# i3dPDK_A16K CFET_3T cell LEF (1x), from BE/CFET/3T/i3dPDK_A16K_0V7_27C_3T.lef:
# SITE i3d_16A added, coordinates on the 0.5nm grid (signal pins snapped outward, OBS outward).
# i3dPDK_A16K v1.0 (CC BY-NC-SA 4.0, Prof. Taigon Song, I3D VLSI Lab, KNU)
# Read after i3dPDK_A16K_3T_tech.lef.
VERSION 5.8 ;
BUSBITCHARS "[]" ;
DIVIDERCHAR "/" ;


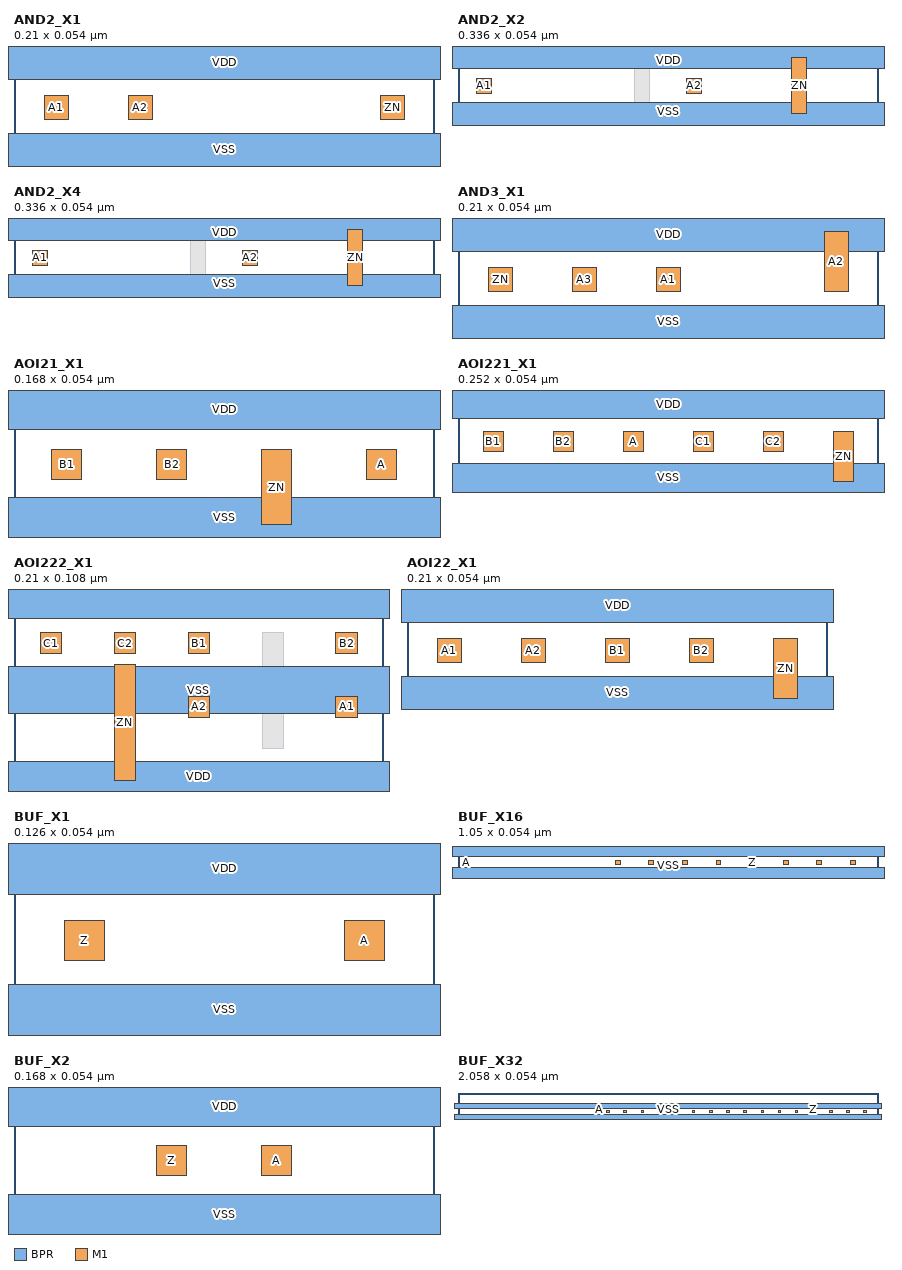
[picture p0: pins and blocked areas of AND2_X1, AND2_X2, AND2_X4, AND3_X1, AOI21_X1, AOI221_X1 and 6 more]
MACRO AND2_X1
  CLASS CORE ;
  FOREIGN AND2_X1 0 0 ;
  ORIGIN 0.0000 0.0000 ;
  SIZE 0.2100 BY 0.0540 ;
  SYMMETRY X Y ;
  SITE i3d_16A ;
  PIN VSS
    DIRECTION INOUT ;
    USE GROUND ;
    PORT
      LAYER BPR ;
        RECT -0.0160 -0.0135 0.2260 0.0135 ;
    END
  END VSS
  PIN VDD
    DIRECTION INOUT ;
    USE POWER ;
    PORT
      LAYER BPR ;
        RECT -0.0160 0.0405 0.2260 0.0675 ;
    END
  END VDD
  PIN A2
    DIRECTION INPUT ;
    USE SIGNAL ;
    PORT
      LAYER M1 ;
        RECT 0.0570 0.0205 0.0690 0.0325 ;
    END
  END A2
  PIN A1
    DIRECTION INPUT ;
    USE SIGNAL ;
    PORT
      LAYER M1 ;
        RECT 0.0150 0.0205 0.0270 0.0325 ;
    END
  END A1
  PIN ZN
    DIRECTION OUTPUT ;
    USE SIGNAL ;
    PORT
      LAYER M1 ;
        RECT 0.1830 0.0205 0.1950 0.0325 ;
    END
  END ZN
END AND2_X1

MACRO AND2_X2
  CLASS CORE ;
  FOREIGN AND2_X2 0 0 ;
  ORIGIN 0.0000 0.0000 ;
  SIZE 0.3360 BY 0.0540 ;
  SYMMETRY X Y ;
  SITE i3d_16A ;
  PIN VSS
    DIRECTION INOUT ;
    USE GROUND ;
    PORT
      LAYER BPR ;
        RECT -0.0160 -0.0135 0.3530 0.0135 ;
    END
  END VSS
  PIN VDD
    DIRECTION INOUT ;
    USE POWER ;
    PORT
      LAYER BPR ;
        RECT -0.0160 0.0405 0.3530 0.0675 ;
    END
  END VDD
  PIN A2
    DIRECTION INPUT ;
    USE SIGNAL ;
    PORT
      LAYER M1 ;
        RECT 0.1830 0.0205 0.1950 0.0325 ;
    END
  END A2
  PIN A1
    DIRECTION INPUT ;
    USE SIGNAL ;
    PORT
      LAYER M1 ;
        RECT 0.0150 0.0205 0.0270 0.0325 ;
    END
  END A1
  PIN ZN
    DIRECTION OUTPUT ;
    USE SIGNAL ;
    PORT
      LAYER M1 ;
        RECT 0.2670 0.0045 0.2790 0.0495 ;
    END
  END ZN
  OBS
    LAYER M1 ;
      RECT 0.1410 0.0025 0.1530 0.0505 ;
  END
END AND2_X2

MACRO AND2_X4
  CLASS CORE ;
  FOREIGN AND2_X4 0 0 ;
  ORIGIN 0.0000 0.0000 ;
  SIZE 0.3360 BY 0.0540 ;
  SYMMETRY X Y ;
  SITE i3d_16A ;
  PIN VSS
    DIRECTION INOUT ;
    USE GROUND ;
    PORT
      LAYER BPR ;
        RECT -0.0160 -0.0135 0.3530 0.0135 ;
    END
  END VSS
  PIN VDD
    DIRECTION INOUT ;
    USE POWER ;
    PORT
      LAYER BPR ;
        RECT -0.0160 0.0405 0.3530 0.0675 ;
    END
  END VDD
  PIN A2
    DIRECTION INPUT ;
    USE SIGNAL ;
    PORT
      LAYER M1 ;
        RECT 0.1830 0.0205 0.1950 0.0325 ;
    END
  END A2
  PIN A1
    DIRECTION INPUT ;
    USE SIGNAL ;
    PORT
      LAYER M1 ;
        RECT 0.0150 0.0205 0.0270 0.0325 ;
    END
  END A1
  PIN ZN
    DIRECTION OUTPUT ;
    USE SIGNAL ;
    PORT
      LAYER M1 ;
        RECT 0.2670 0.0045 0.2790 0.0495 ;
    END
  END ZN
  OBS
    LAYER M1 ;
      RECT 0.1410 0.0025 0.1530 0.0505 ;
  END
END AND2_X4

MACRO AND3_X1
  CLASS CORE ;
  FOREIGN AND3_X1 0 0 ;
  ORIGIN 0.0000 0.0000 ;
  SIZE 0.2100 BY 0.0540 ;
  SYMMETRY X Y ;
  SITE i3d_16A ;
  PIN VDD
    DIRECTION INOUT ;
    USE POWER ;
    PORT
      LAYER BPR ;
        RECT -0.0160 0.0405 0.2260 0.0675 ;
    END
  END VDD
  PIN VSS
    DIRECTION INOUT ;
    USE GROUND ;
    PORT
      LAYER BPR ;
        RECT -0.0160 -0.0135 0.2260 0.0135 ;
    END
  END VSS
  PIN A3
    DIRECTION INPUT ;
    USE SIGNAL ;
    PORT
      LAYER M1 ;
        RECT 0.0570 0.0205 0.0690 0.0325 ;
    END
  END A3
  PIN A1
    DIRECTION INPUT ;
    USE SIGNAL ;
    PORT
      LAYER M1 ;
        RECT 0.0990 0.0205 0.1110 0.0325 ;
    END
  END A1
  PIN ZN
    DIRECTION OUTPUT ;
    USE SIGNAL ;
    PORT
      LAYER M1 ;
        RECT 0.0150 0.0205 0.0270 0.0325 ;
    END
  END ZN
  PIN A2
    DIRECTION INPUT ;
    USE SIGNAL ;
    PORT
      LAYER M1 ;
        RECT 0.1830 0.0205 0.1950 0.0505 ;
    END
  END A2
END AND3_X1

MACRO AOI21_X1
  CLASS CORE ;
  FOREIGN AOI21_X1 0 0 ;
  ORIGIN 0.0000 0.0000 ;
  SIZE 0.1680 BY 0.0540 ;
  SYMMETRY X Y ;
  SITE i3d_16A ;
  PIN VSS
    DIRECTION INOUT ;
    USE GROUND ;
    PORT
      LAYER BPR ;
        RECT -0.0160 -0.0135 0.1840 0.0135 ;
    END
  END VSS
  PIN VDD
    DIRECTION INOUT ;
    USE POWER ;
    PORT
      LAYER BPR ;
        RECT -0.0160 0.0405 0.1840 0.0675 ;
    END
  END VDD
  PIN B2
    DIRECTION INPUT ;
    USE SIGNAL ;
    PORT
      LAYER M1 ;
        RECT 0.0570 0.0205 0.0690 0.0325 ;
    END
  END B2
  PIN B1
    DIRECTION INPUT ;
    USE SIGNAL ;
    PORT
      LAYER M1 ;
        RECT 0.0150 0.0205 0.0270 0.0325 ;
    END
  END B1
  PIN ZN
    DIRECTION OUTPUT ;
    USE SIGNAL ;
    PORT
      LAYER M1 ;
        RECT 0.0990 0.0025 0.1110 0.0325 ;
    END
  END ZN
  PIN A
    DIRECTION INPUT ;
    USE SIGNAL ;
    PORT
      LAYER M1 ;
        RECT 0.1410 0.0205 0.1530 0.0325 ;
    END
  END A
END AOI21_X1

MACRO AOI221_X1
  CLASS CORE ;
  FOREIGN AOI221_X1 0 0 ;
  ORIGIN 0.0000 0.0000 ;
  SIZE 0.2520 BY 0.0540 ;
  SYMMETRY X Y ;
  SITE i3d_16A ;
  PIN VSS
    DIRECTION INOUT ;
    USE GROUND ;
    PORT
      LAYER BPR ;
        RECT -0.0160 -0.0135 0.2680 0.0135 ;
    END
  END VSS
  PIN VDD
    DIRECTION INOUT ;
    USE POWER ;
    PORT
      LAYER BPR ;
        RECT -0.0160 0.0405 0.2680 0.0675 ;
    END
  END VDD
  PIN C2
    DIRECTION INPUT ;
    USE SIGNAL ;
    PORT
      LAYER M1 ;
        RECT 0.1830 0.0205 0.1950 0.0325 ;
    END
  END C2
  PIN A
    DIRECTION INPUT ;
    USE SIGNAL ;
    PORT
      LAYER M1 ;
        RECT 0.0990 0.0205 0.1110 0.0325 ;
    END
  END A
  PIN C1
    DIRECTION INPUT ;
    USE SIGNAL ;
    PORT
      LAYER M1 ;
        RECT 0.1410 0.0205 0.1530 0.0325 ;
    END
  END C1
  PIN B1
    DIRECTION INPUT ;
    USE SIGNAL ;
    PORT
      LAYER M1 ;
        RECT 0.0150 0.0205 0.0270 0.0325 ;
    END
  END B1
  PIN ZN
    DIRECTION OUTPUT ;
    USE SIGNAL ;
    PORT
      LAYER M1 ;
        RECT 0.2250 0.0025 0.2370 0.0325 ;
    END
  END ZN
  PIN B2
    DIRECTION INPUT ;
    USE SIGNAL ;
    PORT
      LAYER M1 ;
        RECT 0.0570 0.0205 0.0690 0.0325 ;
    END
  END B2
END AOI221_X1

MACRO AOI222_X1
  CLASS CORE ;
  FOREIGN AOI222_X1 0 0 ;
  ORIGIN 0.0000 0.0000 ;
  SIZE 0.2100 BY 0.1080 ;
  SYMMETRY X Y ;
  SITE i3d_16A ;
  PIN VDD
    DIRECTION INOUT ;
    USE POWER ;
    PORT
      LAYER BPR ;
        RECT -0.0160 -0.0135 0.2260 0.0135 ;
        RECT -0.0160 0.0945 0.2260 0.1215 ;
    END
  END VDD
  PIN VSS
    DIRECTION INOUT ;
    USE GROUND ;
    PORT
      LAYER BPR ;
        RECT -0.0160 0.0405 0.2260 0.0675 ;
    END
  END VSS
  PIN ZN
    DIRECTION OUTPUT ;
    USE SIGNAL ;
    PORT
      LAYER M1 ;
        RECT 0.0570 0.0025 0.0690 0.0685 ;
    END
  END ZN
  PIN A2
    DIRECTION INPUT ;
    USE SIGNAL ;
    PORT
      LAYER M1 ;
        RECT 0.0990 0.0385 0.1110 0.0505 ;
    END
  END A2
  PIN A1
    DIRECTION INPUT ;
    USE SIGNAL ;
    PORT
      LAYER M1 ;
        RECT 0.1830 0.0385 0.1950 0.0505 ;
    END
  END A1
  PIN B1
    DIRECTION INPUT ;
    USE SIGNAL ;
    PORT
      LAYER M1 ;
        RECT 0.0990 0.0745 0.1110 0.0865 ;
    END
  END B1
  PIN B2
    DIRECTION INPUT ;
    USE SIGNAL ;
    PORT
      LAYER M1 ;
        RECT 0.1830 0.0745 0.1950 0.0865 ;
    END
  END B2
  PIN C1
    DIRECTION INPUT ;
    USE SIGNAL ;
    PORT
      LAYER M1 ;
        RECT 0.0150 0.0745 0.0270 0.0865 ;
    END
  END C1
  PIN C2
    DIRECTION INPUT ;
    USE SIGNAL ;
    PORT
      LAYER M1 ;
        RECT 0.0570 0.0745 0.0690 0.0865 ;
    END
  END C2
  OBS
    LAYER M1 ;
      RECT 0.1410 0.0205 0.1530 0.0325 ;
      RECT 0.1410 0.0205 0.1530 0.0865 ;
  END
END AOI222_X1

MACRO AOI22_X1
  CLASS CORE ;
  FOREIGN AOI22_X1 0 0 ;
  ORIGIN 0.0000 0.0000 ;
  SIZE 0.2100 BY 0.0540 ;
  SYMMETRY X Y ;
  SITE i3d_16A ;
  PIN VDD
    DIRECTION INOUT ;
    USE POWER ;
    PORT
      LAYER BPR ;
        RECT -0.0160 0.0405 0.2260 0.0675 ;
    END
  END VDD
  PIN VSS
    DIRECTION INOUT ;
    USE GROUND ;
    PORT
      LAYER BPR ;
        RECT -0.0160 -0.0135 0.2260 0.0135 ;
    END
  END VSS
  PIN A2
    DIRECTION INPUT ;
    USE SIGNAL ;
    PORT
      LAYER M1 ;
        RECT 0.0570 0.0205 0.0690 0.0325 ;
    END
  END A2
  PIN ZN
    DIRECTION OUTPUT ;
    USE SIGNAL ;
    PORT
      LAYER M1 ;
        RECT 0.1830 0.0025 0.1950 0.0325 ;
    END
  END ZN
  PIN A1
    DIRECTION INPUT ;
    USE SIGNAL ;
    PORT
      LAYER M1 ;
        RECT 0.0150 0.0205 0.0270 0.0325 ;
    END
  END A1
  PIN B2
    DIRECTION INPUT ;
    USE SIGNAL ;
    PORT
      LAYER M1 ;
        RECT 0.1410 0.0205 0.1530 0.0325 ;
    END
  END B2
  PIN B1
    DIRECTION INPUT ;
    USE SIGNAL ;
    PORT
      LAYER M1 ;
        RECT 0.0990 0.0205 0.1110 0.0325 ;
    END
  END B1
END AOI22_X1

MACRO BUF_X1
  CLASS CORE ;
  FOREIGN BUF_X1 0 0 ;
  ORIGIN 0.0000 0.0000 ;
  SIZE 0.1260 BY 0.0540 ;
  SYMMETRY X Y ;
  SITE i3d_16A ;
  PIN VSS
    DIRECTION INOUT ;
    USE GROUND ;
    PORT
      LAYER BPR ;
        RECT -0.0160 -0.0135 0.1420 0.0135 ;
    END
  END VSS
  PIN VDD
    DIRECTION INOUT ;
    USE POWER ;
    PORT
      LAYER BPR ;
        RECT -0.0160 0.0405 0.1420 0.0675 ;
    END
  END VDD
  PIN Z
    DIRECTION OUTPUT ;
    USE SIGNAL ;
    PORT
      LAYER M1 ;
        RECT 0.0150 0.0205 0.0270 0.0325 ;
    END
  END Z
  PIN A
    DIRECTION INPUT ;
    USE SIGNAL ;
    PORT
      LAYER M1 ;
        RECT 0.0990 0.0205 0.1110 0.0325 ;
    END
  END A
END BUF_X1

MACRO BUF_X16
  CLASS CORE ;
  FOREIGN BUF_X16 0 0 ;
  ORIGIN 0.0000 0.0000 ;
  SIZE 1.0500 BY 0.0540 ;
  SYMMETRY X Y ;
  SITE i3d_16A ;
  PIN VDD
    DIRECTION INOUT ;
    USE POWER ;
    PORT
      LAYER BPR ;
        RECT -0.0160 0.0405 1.0660 0.0675 ;
    END
  END VDD
  PIN VSS
    DIRECTION INOUT ;
    USE GROUND ;
    PORT
      LAYER BPR ;
        RECT -0.0160 -0.0135 1.0660 0.0135 ;
    END
  END VSS
  PIN Z
    DIRECTION OUTPUT ;
    USE SIGNAL ;
    PORT
      LAYER M1 ;
        RECT 0.7290 0.0205 0.7410 0.0325 ;
        RECT 0.8130 0.0205 0.8250 0.0325 ;
        RECT 0.9810 0.0205 0.9930 0.0325 ;
        RECT 0.8970 0.0205 0.9090 0.0325 ;
        RECT 0.4770 0.0205 0.4890 0.0325 ;
        RECT 0.3930 0.0205 0.4050 0.0325 ;
        RECT 0.6450 0.0205 0.6570 0.0325 ;
        RECT 0.5610 0.0205 0.5730 0.0325 ;
    END
  END Z
  PIN A
    DIRECTION INPUT ;
    USE SIGNAL ;
    PORT
      LAYER M1 ;
        RECT 0.0150 0.0205 0.0270 0.0325 ;
    END
  END A
END BUF_X16

MACRO BUF_X2
  CLASS CORE ;
  FOREIGN BUF_X2 0 0 ;
  ORIGIN 0.0000 0.0000 ;
  SIZE 0.1680 BY 0.0540 ;
  SYMMETRY X Y ;
  SITE i3d_16A ;
  PIN VDD
    DIRECTION INOUT ;
    USE POWER ;
    PORT
      LAYER BPR ;
        RECT -0.0160 0.0405 0.1840 0.0675 ;
    END
  END VDD
  PIN VSS
    DIRECTION INOUT ;
    USE GROUND ;
    PORT
      LAYER BPR ;
        RECT -0.0160 -0.0135 0.1840 0.0135 ;
    END
  END VSS
  PIN A
    DIRECTION INPUT ;
    USE SIGNAL ;
    PORT
      LAYER M1 ;
        RECT 0.0990 0.0210 0.1110 0.0330 ;
    END
  END A
  PIN Z
    DIRECTION OUTPUT ;
    USE SIGNAL ;
    PORT
      LAYER M1 ;
        RECT 0.0570 0.0210 0.0690 0.0330 ;
    END
  END Z
END BUF_X2

MACRO BUF_X32
  CLASS CORE ;
  FOREIGN BUF_X32 0 0 ;
  ORIGIN 0.0000 0.0000 ;
  SIZE 2.0580 BY 0.0540 ;
  SYMMETRY X Y ;
  SITE i3d_16A ;
  PIN VSS
    DIRECTION INOUT ;
    USE GROUND ;
    PORT
      LAYER BPR ;
        RECT -0.0160 -0.0135 2.0740 0.0135 ;
    END
  END VSS
  PIN VDD
    DIRECTION INOUT ;
    USE POWER ;
    PORT
      LAYER BPR ;
        RECT -0.0160 0.0405 2.0740 0.0675 ;
    END
  END VDD
  PIN Z
    DIRECTION OUTPUT ;
    USE SIGNAL ;
    PORT
      LAYER M1 ;
        RECT 1.7370 0.0205 1.7490 0.0325 ;
        RECT 1.8210 0.0205 1.8330 0.0325 ;
        RECT 1.9890 0.0205 2.0010 0.0325 ;
        RECT 1.9050 0.0205 1.9170 0.0325 ;
        RECT 1.4850 0.0205 1.4970 0.0325 ;
        RECT 1.4010 0.0205 1.4130 0.0325 ;
        RECT 1.6530 0.0205 1.6650 0.0325 ;
        RECT 1.5690 0.0205 1.5810 0.0325 ;
        RECT 1.2330 0.0205 1.2450 0.0325 ;
        RECT 1.3170 0.0205 1.3290 0.0325 ;
        RECT 1.1490 0.0205 1.1610 0.0325 ;
        RECT 1.0650 0.0205 1.0770 0.0325 ;
        RECT 0.7290 0.0205 0.7410 0.0325 ;
        RECT 0.8130 0.0205 0.8250 0.0325 ;
        RECT 0.9810 0.0205 0.9930 0.0325 ;
        RECT 0.8970 0.0205 0.9090 0.0325 ;
    END
  END Z
  PIN A
    DIRECTION INPUT ;
    USE SIGNAL ;
    PORT
      LAYER M1 ;
        RECT 0.6870 0.0205 0.6990 0.0325 ;
    END
  END A
END BUF_X32

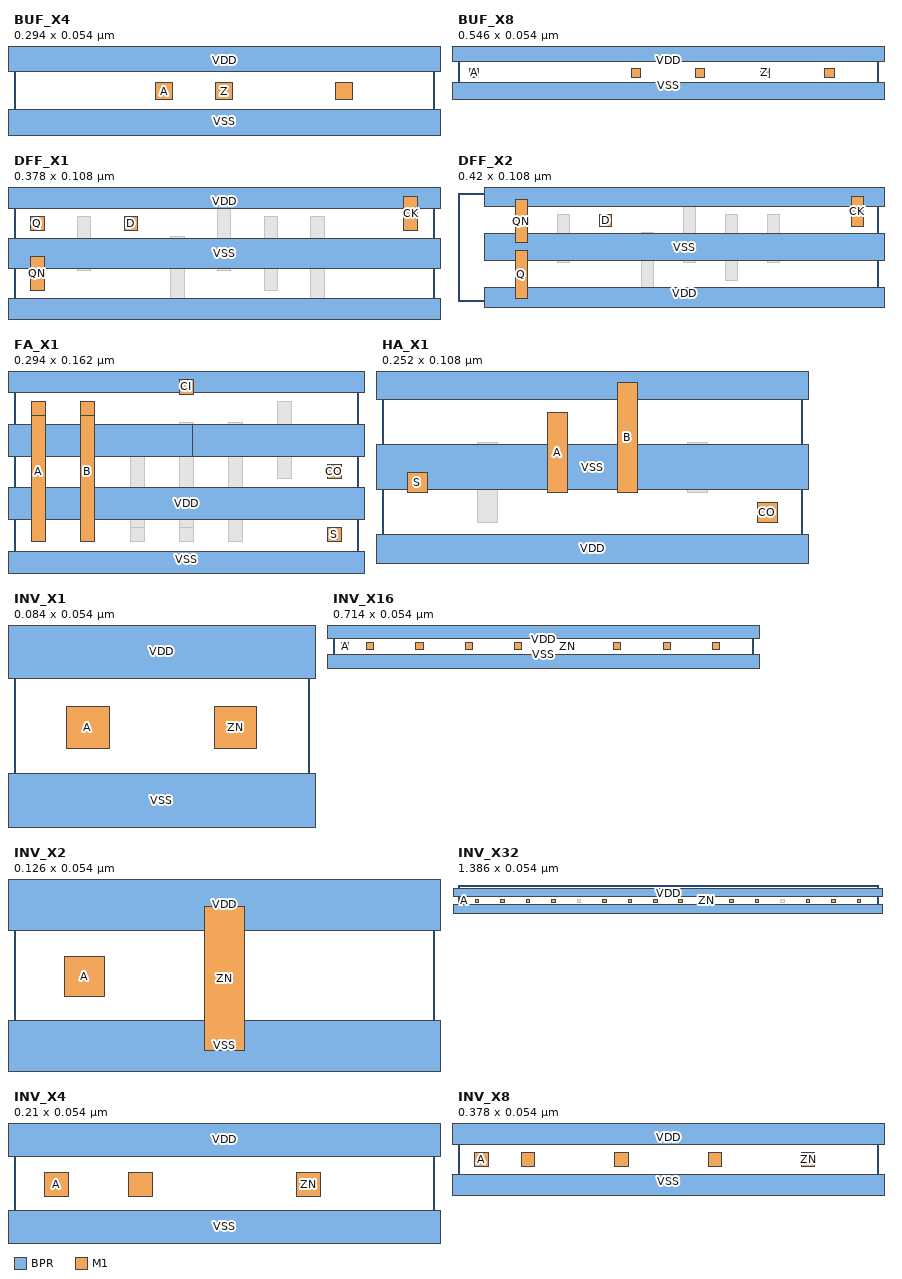
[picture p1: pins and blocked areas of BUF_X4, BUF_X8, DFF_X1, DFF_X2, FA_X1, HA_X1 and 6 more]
MACRO BUF_X4
  CLASS CORE ;
  FOREIGN BUF_X4 0 0 ;
  ORIGIN 0.0000 0.0000 ;
  SIZE 0.2940 BY 0.0540 ;
  SYMMETRY X Y ;
  SITE i3d_16A ;
  PIN VDD
    DIRECTION INOUT ;
    USE POWER ;
    PORT
      LAYER BPR ;
        RECT -0.0160 0.0405 0.3100 0.0675 ;
    END
  END VDD
  PIN VSS
    DIRECTION INOUT ;
    USE GROUND ;
    PORT
      LAYER BPR ;
        RECT -0.0160 -0.0135 0.3100 0.0135 ;
    END
  END VSS
  PIN A
    DIRECTION INPUT ;
    USE SIGNAL ;
    PORT
      LAYER M1 ;
        RECT 0.0990 0.0205 0.1110 0.0325 ;
    END
  END A
  PIN Z
    DIRECTION OUTPUT ;
    USE SIGNAL ;
    PORT
      LAYER M1 ;
        RECT 0.2250 0.0205 0.2370 0.0325 ;
        RECT 0.1410 0.0205 0.1530 0.0325 ;
    END
  END Z
END BUF_X4

MACRO BUF_X8
  CLASS CORE ;
  FOREIGN BUF_X8 0 0 ;
  ORIGIN 0.0000 0.0000 ;
  SIZE 0.5460 BY 0.0540 ;
  SYMMETRY X Y ;
  SITE i3d_16A ;
  PIN VSS
    DIRECTION INOUT ;
    USE GROUND ;
    PORT
      LAYER BPR ;
        RECT -0.0160 -0.0135 0.5620 0.0135 ;
    END
  END VSS
  PIN VDD
    DIRECTION INOUT ;
    USE POWER ;
    PORT
      LAYER BPR ;
        RECT -0.0160 0.0405 0.5620 0.0675 ;
    END
  END VDD
  PIN Z
    DIRECTION OUTPUT ;
    USE SIGNAL ;
    PORT
      LAYER M1 ;
        RECT 0.3930 0.0205 0.4050 0.0325 ;
        RECT 0.4770 0.0205 0.4890 0.0325 ;
        RECT 0.3090 0.0205 0.3210 0.0325 ;
        RECT 0.2250 0.0205 0.2370 0.0325 ;
    END
  END Z
  PIN A
    DIRECTION INPUT ;
    USE SIGNAL ;
    PORT
      LAYER M1 ;
        RECT 0.0150 0.0205 0.0270 0.0325 ;
    END
  END A
END BUF_X8

MACRO DFF_X1
  CLASS CORE ;
  FOREIGN DFF_X1 0 0 ;
  ORIGIN 0.0000 0.0000 ;
  SIZE 0.3780 BY 0.1080 ;
  SYMMETRY X Y ;
  SITE i3d_16A ;
  PIN VDD
    DIRECTION INOUT ;
    USE POWER ;
    PORT
      LAYER BPR ;
        RECT -0.0160 0.0945 0.3940 0.1215 ;
        RECT -0.0160 -0.0135 0.3940 0.0135 ;
    END
  END VDD
  PIN VSS
    DIRECTION INOUT ;
    USE GROUND ;
    PORT
      LAYER BPR ;
        RECT -0.0160 0.0405 0.3940 0.0675 ;
    END
  END VSS
  PIN CK
    DIRECTION INPUT ;
    USE CLOCK ;
    PORT
      LAYER M1 ;
        RECT 0.3510 0.0745 0.3630 0.1045 ;
    END
  END CK
  PIN D
    DIRECTION INPUT ;
    USE SIGNAL ;
    PORT
      LAYER M1 ;
        RECT 0.0990 0.0745 0.1110 0.0865 ;
    END
  END D
  PIN QN
    DIRECTION OUTPUT ;
    USE SIGNAL ;
    PORT
      LAYER M1 ;
        RECT 0.0150 0.0205 0.0270 0.0505 ;
    END
  END QN
  PIN Q
    DIRECTION OUTPUT ;
    USE SIGNAL ;
    PORT
      LAYER M1 ;
        RECT 0.0150 0.0745 0.0270 0.0865 ;
    END
  END Q
  OBS
    LAYER M1 ;
      RECT 0.2250 0.0205 0.2370 0.0865 ;
      RECT 0.1410 0.0025 0.1530 0.0685 ;
      RECT 0.2670 0.0025 0.2790 0.0865 ;
      RECT 0.1830 0.0385 0.1950 0.1045 ;
      RECT 0.0570 0.0385 0.0690 0.0865 ;
  END
END DFF_X1

MACRO DFF_X2
  CLASS CORE ;
  FOREIGN DFF_X2 0 0 ;
  ORIGIN 0.0000 0.0000 ;
  SIZE 0.4200 BY 0.1080 ;
  SYMMETRY X Y ;
  SITE i3d_16A ;
  PIN VDD
    DIRECTION INOUT ;
    USE POWER ;
    PORT
      LAYER BPR ;
        RECT 0.0260 0.0945 0.4360 0.1215 ;
        RECT 0.0260 -0.0135 0.4360 0.0135 ;
    END
  END VDD
  PIN VSS
    DIRECTION INOUT ;
    USE GROUND ;
    PORT
      LAYER BPR ;
        RECT 0.0260 0.0405 0.4360 0.0675 ;
    END
  END VSS
  PIN CK
    DIRECTION INPUT ;
    USE CLOCK ;
    PORT
      LAYER M1 ;
        RECT 0.3930 0.0745 0.4050 0.1045 ;
    END
  END CK
  PIN D
    DIRECTION INPUT ;
    USE SIGNAL ;
    PORT
      LAYER M1 ;
        RECT 0.1410 0.0745 0.1530 0.0865 ;
    END
  END D
  PIN QN
    DIRECTION OUTPUT ;
    USE SIGNAL ;
    PORT
      LAYER M1 ;
        RECT 0.0570 0.0585 0.0690 0.1015 ;
    END
  END QN
  PIN Q
    DIRECTION OUTPUT ;
    USE SIGNAL ;
    PORT
      LAYER M1 ;
        RECT 0.0570 0.0025 0.0690 0.0505 ;
    END
  END Q
  OBS
    LAYER M1 ;
      RECT 0.2670 0.0205 0.2790 0.0865 ;
      RECT 0.1830 0.0025 0.1950 0.0685 ;
      RECT 0.3090 0.0385 0.3210 0.0865 ;
      RECT 0.2250 0.0385 0.2370 0.1045 ;
      RECT 0.0990 0.0385 0.1110 0.0865 ;
  END
END DFF_X2

MACRO FA_X1
  CLASS CORE ;
  FOREIGN FA_X1 0 0 ;
  ORIGIN 0.0000 0.0000 ;
  SIZE 0.2940 BY 0.1620 ;
  SYMMETRY X Y ;
  SITE i3d_16A ;
  PIN VDD
    DIRECTION INOUT ;
    USE POWER ;
    PORT
      LAYER BPR ;
        RECT 0.0260 0.0405 0.3100 0.0675 ;
        RECT -0.0160 0.1485 0.3100 0.1755 ;
        RECT -0.0160 0.0405 0.3100 0.0675 ;
    END
  END VDD
  PIN VSS
    DIRECTION INOUT ;
    USE GROUND ;
    PORT
      LAYER BPR ;
        RECT -0.0160 0.0945 0.3100 0.1215 ;
        RECT 0.0260 0.0945 0.2260 0.1215 ;
        RECT -0.0160 -0.0135 0.3100 0.0135 ;
        RECT 0.1520 0.0945 0.3100 0.1215 ;
    END
  END VSS
  PIN B
    DIRECTION INPUT ;
    USE SIGNAL ;
    PORT
      LAYER M1 ;
        RECT 0.0570 0.0215 0.0690 0.1415 ;
        RECT 0.0570 0.1295 0.0690 0.1415 ;
    END
  END B
  PIN A
    DIRECTION INPUT ;
    USE SIGNAL ;
    PORT
      LAYER M1 ;
        RECT 0.0150 0.1295 0.0270 0.1415 ;
        RECT 0.0150 0.1295 0.0270 0.1415 ;
        RECT 0.0150 0.0215 0.0270 0.1415 ;
    END
  END A
  PIN CI
    DIRECTION INPUT ;
    USE SIGNAL ;
    PORT
      LAYER M1 ;
        RECT 0.1410 0.1475 0.1530 0.1595 ;
    END
  END CI
  PIN CO
    DIRECTION OUTPUT ;
    USE SIGNAL ;
    PORT
      LAYER M1 ;
        RECT 0.2670 0.0755 0.2790 0.0875 ;
    END
  END CO
  PIN S
    DIRECTION OUTPUT ;
    USE SIGNAL ;
    PORT
      LAYER M1 ;
        RECT 0.2670 0.0215 0.2790 0.0335 ;
    END
  END S
  OBS
    LAYER M1 ;
      RECT 0.0990 0.0215 0.1110 0.1055 ;
      RECT 0.1410 0.0215 0.1530 0.1235 ;
      RECT 0.1830 0.0215 0.1950 0.1055 ;
      RECT 0.0990 0.0215 0.1110 0.0335 ;
      RECT 0.0570 0.0215 0.0690 0.0335 ;
      RECT 0.0150 0.0215 0.0270 0.0335 ;
      RECT 0.1410 0.0215 0.1530 0.0335 ;
      RECT 0.1830 0.1115 0.1950 0.1235 ;
      RECT 0.2250 0.0755 0.2370 0.1415 ;
  END
END FA_X1

MACRO HA_X1
  CLASS CORE ;
  FOREIGN HA_X1 0 0 ;
  ORIGIN 0.0000 0.0000 ;
  SIZE 0.2520 BY 0.1080 ;
  SYMMETRY X Y ;
  SITE i3d_16A ;
  PIN VSS
    DIRECTION INOUT ;
    USE GROUND ;
    PORT
      LAYER BPR ;
        RECT -0.0160 0.0405 0.2680 0.0675 ;
    END
  END VSS
  PIN VDD
    DIRECTION INOUT ;
    USE POWER ;
    PORT
      LAYER BPR ;
        RECT -0.0160 0.0945 0.2680 0.1215 ;
        RECT -0.0160 -0.0135 0.2680 0.0135 ;
    END
  END VDD
  PIN S
    DIRECTION OUTPUT ;
    USE SIGNAL ;
    PORT
      LAYER M1 ;
        RECT 0.0150 0.0390 0.0270 0.0510 ;
    END
  END S
  PIN CO
    DIRECTION OUTPUT ;
    USE SIGNAL ;
    PORT
      LAYER M1 ;
        RECT 0.2250 0.0210 0.2370 0.0330 ;
    END
  END CO
  PIN A
    DIRECTION INPUT ;
    USE SIGNAL ;
    PORT
      LAYER M1 ;
        RECT 0.0990 0.0390 0.1110 0.0870 ;
    END
  END A
  PIN B
    DIRECTION INPUT ;
    USE SIGNAL ;
    PORT
      LAYER M1 ;
        RECT 0.1410 0.0390 0.1530 0.1050 ;
    END
  END B
  OBS
    LAYER M1 ;
      RECT 0.0570 0.0210 0.0690 0.0690 ;
      RECT 0.1830 0.0390 0.1950 0.0690 ;
  END
END HA_X1

MACRO INV_X1
  CLASS CORE ;
  FOREIGN INV_X1 0 0 ;
  ORIGIN 0.0000 0.0000 ;
  SIZE 0.0840 BY 0.0540 ;
  SYMMETRY X Y ;
  SITE i3d_16A ;
  PIN VDD
    DIRECTION INOUT ;
    USE POWER ;
    PORT
      LAYER BPR ;
        RECT -0.0160 0.0405 0.1000 0.0675 ;
    END
  END VDD
  PIN VSS
    DIRECTION INOUT ;
    USE GROUND ;
    PORT
      LAYER BPR ;
        RECT -0.0160 -0.0135 0.1000 0.0135 ;
    END
  END VSS
  PIN A
    DIRECTION INPUT ;
    USE SIGNAL ;
    PORT
      LAYER M1 ;
        RECT 0.0150 0.0205 0.0270 0.0325 ;
    END
  END A
  PIN ZN
    DIRECTION OUTPUT ;
    USE SIGNAL ;
    PORT
      LAYER M1 ;
        RECT 0.0570 0.0205 0.0690 0.0325 ;
    END
  END ZN
END INV_X1

MACRO INV_X16
  CLASS CORE ;
  FOREIGN INV_X16 0 0 ;
  ORIGIN 0.0000 0.0000 ;
  SIZE 0.7140 BY 0.0540 ;
  SYMMETRY X Y ;
  SITE i3d_16A ;
  PIN VDD
    DIRECTION INOUT ;
    USE POWER ;
    PORT
      LAYER BPR ;
        RECT -0.0160 0.0405 0.7300 0.0675 ;
    END
  END VDD
  PIN VSS
    DIRECTION INOUT ;
    USE GROUND ;
    PORT
      LAYER BPR ;
        RECT -0.0160 -0.0135 0.7300 0.0135 ;
    END
  END VSS
  PIN ZN
    DIRECTION OUTPUT ;
    USE SIGNAL ;
    PORT
      LAYER M1 ;
        RECT 0.3930 0.0205 0.4050 0.0325 ;
        RECT 0.4770 0.0205 0.4890 0.0325 ;
        RECT 0.6450 0.0205 0.6570 0.0325 ;
        RECT 0.5610 0.0205 0.5730 0.0325 ;
        RECT 0.1410 0.0205 0.1530 0.0325 ;
        RECT 0.0570 0.0205 0.0690 0.0325 ;
        RECT 0.2250 0.0205 0.2370 0.0325 ;
        RECT 0.3090 0.0205 0.3210 0.0325 ;
    END
  END ZN
  PIN A
    DIRECTION INPUT ;
    USE SIGNAL ;
    PORT
      LAYER M1 ;
        RECT 0.0150 0.0205 0.0270 0.0325 ;
    END
  END A
END INV_X16

MACRO INV_X2
  CLASS CORE ;
  FOREIGN INV_X2 0 0 ;
  ORIGIN 0.0000 0.0000 ;
  SIZE 0.1260 BY 0.0540 ;
  SYMMETRY X Y ;
  SITE i3d_16A ;
  PIN VSS
    DIRECTION INOUT ;
    USE GROUND ;
    PORT
      LAYER BPR ;
        RECT -0.0160 -0.0135 0.1420 0.0135 ;
    END
  END VSS
  PIN VDD
    DIRECTION INOUT ;
    USE POWER ;
    PORT
      LAYER BPR ;
        RECT -0.0160 0.0405 0.1420 0.0675 ;
    END
  END VDD
  PIN ZN
    DIRECTION OUTPUT ;
    USE SIGNAL ;
    PORT
      LAYER M1 ;
        RECT 0.0570 0.0045 0.0690 0.0475 ;
    END
  END ZN
  PIN A
    DIRECTION INPUT ;
    USE SIGNAL ;
    PORT
      LAYER M1 ;
        RECT 0.0150 0.0205 0.0270 0.0325 ;
    END
  END A
END INV_X2

MACRO INV_X32
  CLASS CORE ;
  FOREIGN INV_X32 0 0 ;
  ORIGIN 0.0000 0.0000 ;
  SIZE 1.3860 BY 0.0540 ;
  SYMMETRY X Y ;
  SITE i3d_16A ;
  PIN VSS
    DIRECTION INOUT ;
    USE GROUND ;
    PORT
      LAYER BPR ;
        RECT -0.0160 -0.0135 1.4020 0.0135 ;
    END
  END VSS
  PIN VDD
    DIRECTION INOUT ;
    USE POWER ;
    PORT
      LAYER BPR ;
        RECT -0.0160 0.0405 1.4020 0.0675 ;
    END
  END VDD
  PIN ZN
    DIRECTION OUTPUT ;
    USE SIGNAL ;
    PORT
      LAYER M1 ;
        RECT 0.8130 0.0205 0.8250 0.0325 ;
        RECT 0.7290 0.0205 0.7410 0.0325 ;
        RECT 0.8970 0.0205 0.9090 0.0325 ;
        RECT 0.9810 0.0205 0.9930 0.0325 ;
        RECT 1.1490 0.0205 1.1610 0.0325 ;
        RECT 1.3170 0.0205 1.3290 0.0325 ;
        RECT 1.2330 0.0205 1.2450 0.0325 ;
        RECT 0.3090 0.0205 0.3210 0.0325 ;
        RECT 0.2250 0.0205 0.2370 0.0325 ;
        RECT 0.0570 0.0205 0.0690 0.0325 ;
        RECT 0.1410 0.0205 0.1530 0.0325 ;
        RECT 0.5610 0.0205 0.5730 0.0325 ;
        RECT 0.6450 0.0205 0.6570 0.0325 ;
        RECT 0.4770 0.0205 0.4890 0.0325 ;
    END
  END ZN
  PIN A
    DIRECTION INPUT ;
    USE SIGNAL ;
    PORT
      LAYER M1 ;
        RECT 0.0150 0.0205 0.0270 0.0325 ;
    END
  END A
  OBS
    LAYER M1 ;
      RECT 1.0650 0.0205 1.0770 0.0325 ;
      RECT 0.3930 0.0205 0.4050 0.0325 ;
  END
END INV_X32

MACRO INV_X4
  CLASS CORE ;
  FOREIGN INV_X4 0 0 ;
  ORIGIN 0.0000 0.0000 ;
  SIZE 0.2100 BY 0.0540 ;
  SYMMETRY X Y ;
  SITE i3d_16A ;
  PIN VDD
    DIRECTION INOUT ;
    USE POWER ;
    PORT
      LAYER BPR ;
        RECT -0.0160 0.0405 0.2260 0.0675 ;
    END
  END VDD
  PIN VSS
    DIRECTION INOUT ;
    USE GROUND ;
    PORT
      LAYER BPR ;
        RECT -0.0160 -0.0135 0.2260 0.0135 ;
    END
  END VSS
  PIN ZN
    DIRECTION OUTPUT ;
    USE SIGNAL ;
    PORT
      LAYER M1 ;
        RECT 0.1410 0.0205 0.1530 0.0325 ;
        RECT 0.0570 0.0205 0.0690 0.0325 ;
    END
  END ZN
  PIN A
    DIRECTION INPUT ;
    USE SIGNAL ;
    PORT
      LAYER M1 ;
        RECT 0.0150 0.0205 0.0270 0.0325 ;
    END
  END A
END INV_X4

MACRO INV_X8
  CLASS CORE ;
  FOREIGN INV_X8 0 0 ;
  ORIGIN 0.0000 0.0000 ;
  SIZE 0.3780 BY 0.0540 ;
  SYMMETRY X Y ;
  SITE i3d_16A ;
  PIN VSS
    DIRECTION INOUT ;
    USE GROUND ;
    PORT
      LAYER BPR ;
        RECT -0.0160 -0.0135 0.3940 0.0135 ;
    END
  END VSS
  PIN VDD
    DIRECTION INOUT ;
    USE POWER ;
    PORT
      LAYER BPR ;
        RECT -0.0160 0.0405 0.3940 0.0675 ;
    END
  END VDD
  PIN ZN
    DIRECTION OUTPUT ;
    USE SIGNAL ;
    PORT
      LAYER M1 ;
        RECT 0.3090 0.0205 0.3210 0.0325 ;
        RECT 0.2250 0.0205 0.2370 0.0325 ;
        RECT 0.0570 0.0205 0.0690 0.0325 ;
        RECT 0.1410 0.0205 0.1530 0.0325 ;
    END
  END ZN
  PIN A
    DIRECTION INPUT ;
    USE SIGNAL ;
    PORT
      LAYER M1 ;
        RECT 0.0150 0.0205 0.0270 0.0325 ;
    END
  END A
END INV_X8

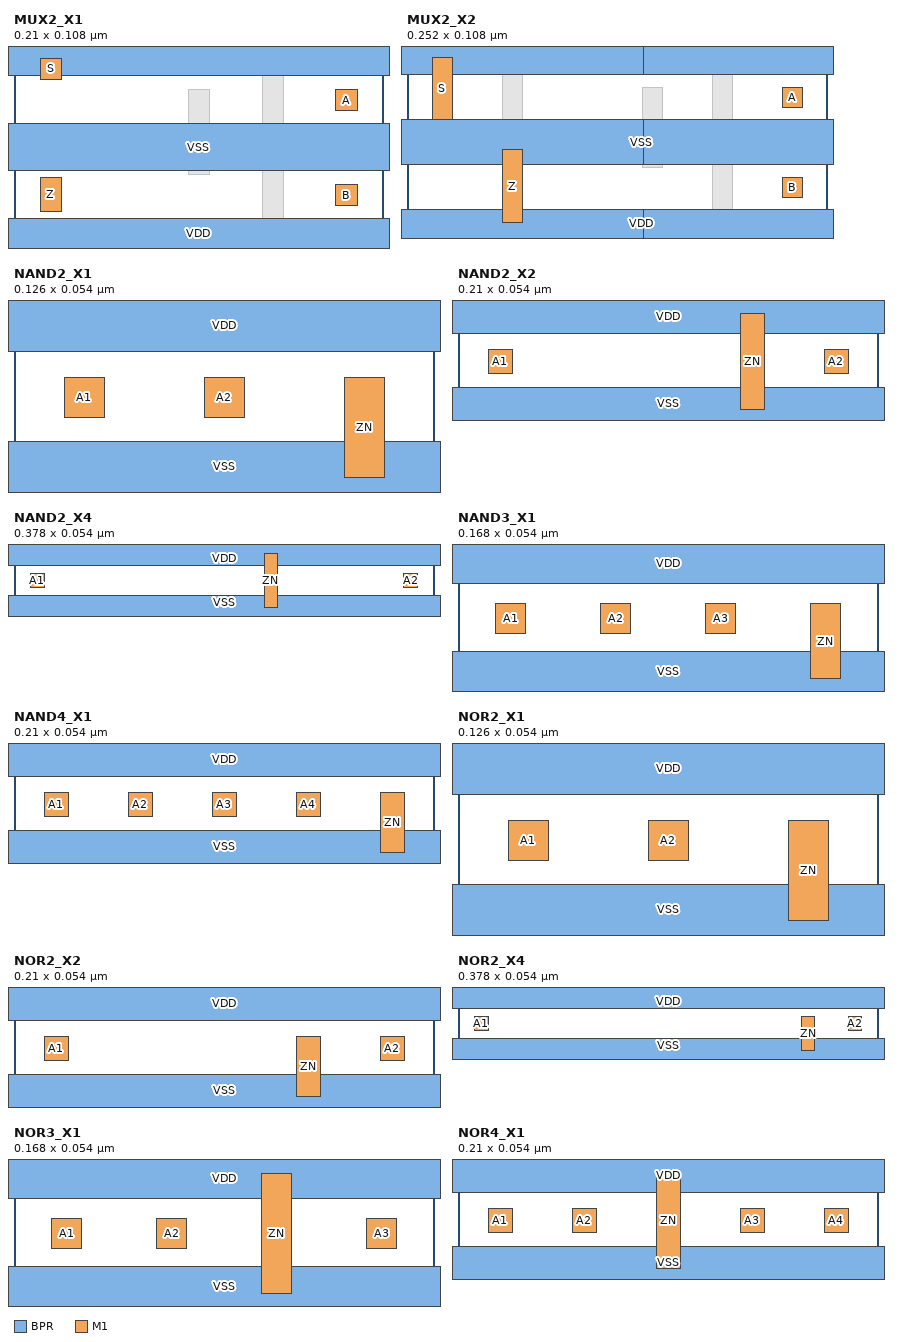
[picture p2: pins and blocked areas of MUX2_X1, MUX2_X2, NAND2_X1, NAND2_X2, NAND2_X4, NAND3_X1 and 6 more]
MACRO MUX2_X1
  CLASS CORE ;
  FOREIGN MUX2_X1 0 0 ;
  ORIGIN 0.0000 0.0000 ;
  SIZE 0.2100 BY 0.1080 ;
  SYMMETRY X Y ;
  SITE i3d_16A ;
  PIN VDD
    DIRECTION INOUT ;
    USE POWER ;
    PORT
      LAYER BPR ;
        RECT -0.0160 0.0945 0.2260 0.1215 ;
        RECT -0.0160 -0.0135 0.2260 0.0135 ;
    END
  END VDD
  PIN VSS
    DIRECTION INOUT ;
    USE GROUND ;
    PORT
      LAYER BPR ;
        RECT -0.0160 0.0405 0.2260 0.0675 ;
    END
  END VSS
  PIN S
    DIRECTION INPUT ;
    USE SIGNAL ;
    PORT
      LAYER M1 ;
        RECT 0.0150 0.0925 0.0270 0.1045 ;
    END
  END S
  PIN A
    DIRECTION INPUT ;
    USE SIGNAL ;
    PORT
      LAYER M1 ;
        RECT 0.1830 0.0745 0.1950 0.0865 ;
    END
  END A
  PIN B
    DIRECTION INPUT ;
    USE SIGNAL ;
    PORT
      LAYER M1 ;
        RECT 0.1830 0.0205 0.1950 0.0325 ;
    END
  END B
  PIN Z
    DIRECTION OUTPUT ;
    USE SIGNAL ;
    PORT
      LAYER M1 ;
        RECT 0.0150 0.0175 0.0270 0.0365 ;
    END
  END Z
  OBS
    LAYER M1 ;
      RECT 0.0990 0.0385 0.1110 0.0865 ;
      RECT 0.1410 0.0025 0.1530 0.1045 ;
  END
END MUX2_X1

MACRO MUX2_X2
  CLASS CORE ;
  FOREIGN MUX2_X2 0 0 ;
  ORIGIN 0.0000 0.0000 ;
  SIZE 0.2520 BY 0.1080 ;
  SYMMETRY X Y ;
  SITE i3d_16A ;
  PIN VDD
    DIRECTION INOUT ;
    USE POWER ;
    PORT
      LAYER BPR ;
        RECT -0.0160 0.0945 0.1420 0.1215 ;
        RECT 0.0260 -0.0135 0.2680 0.0135 ;
        RECT 0.0260 0.0945 0.2680 0.1215 ;
        RECT -0.0160 -0.0135 0.1420 0.0135 ;
    END
  END VDD
  PIN VSS
    DIRECTION INOUT ;
    USE GROUND ;
    PORT
      LAYER BPR ;
        RECT 0.0260 0.0405 0.2680 0.0675 ;
        RECT -0.0160 0.0405 0.1420 0.0675 ;
        RECT -0.0160 0.0405 0.1420 0.0675 ;
    END
  END VSS
  PIN S
    DIRECTION INPUT ;
    USE SIGNAL ;
    PORT
      LAYER M1 ;
        RECT 0.0150 0.0675 0.0270 0.1045 ;
    END
  END S
  PIN A
    DIRECTION INPUT ;
    USE SIGNAL ;
    PORT
      LAYER M1 ;
        RECT 0.2250 0.0745 0.2370 0.0865 ;
    END
  END A
  PIN B
    DIRECTION INPUT ;
    USE SIGNAL ;
    PORT
      LAYER M1 ;
        RECT 0.2250 0.0205 0.2370 0.0325 ;
    END
  END B
  PIN Z
    DIRECTION OUTPUT ;
    USE SIGNAL ;
    PORT
      LAYER M1 ;
        RECT 0.0570 0.0055 0.0690 0.0495 ;
    END
  END Z
  OBS
    LAYER M1 ;
      RECT 0.1830 0.0025 0.1950 0.1045 ;
      RECT 0.1410 0.0385 0.1530 0.0865 ;
      RECT 0.0570 0.0585 0.0690 0.1015 ;
  END
END MUX2_X2

MACRO NAND2_X1
  CLASS CORE ;
  FOREIGN NAND2_X1 0 0 ;
  ORIGIN 0.0000 0.0000 ;
  SIZE 0.1260 BY 0.0540 ;
  SYMMETRY X Y ;
  SITE i3d_16A ;
  PIN VSS
    DIRECTION INOUT ;
    USE GROUND ;
    PORT
      LAYER BPR ;
        RECT -0.0160 -0.0135 0.1420 0.0135 ;
    END
  END VSS
  PIN VDD
    DIRECTION INOUT ;
    USE POWER ;
    PORT
      LAYER BPR ;
        RECT -0.0160 0.0405 0.1420 0.0675 ;
    END
  END VDD
  PIN A2
    DIRECTION INPUT ;
    USE SIGNAL ;
    PORT
      LAYER M1 ;
        RECT 0.0570 0.0205 0.0690 0.0325 ;
    END
  END A2
  PIN A1
    DIRECTION INPUT ;
    USE SIGNAL ;
    PORT
      LAYER M1 ;
        RECT 0.0150 0.0205 0.0270 0.0325 ;
    END
  END A1
  PIN ZN
    DIRECTION OUTPUT ;
    USE SIGNAL ;
    PORT
      LAYER M1 ;
        RECT 0.0990 0.0025 0.1110 0.0325 ;
    END
  END ZN
END NAND2_X1

MACRO NAND2_X2
  CLASS CORE ;
  FOREIGN NAND2_X2 0 0 ;
  ORIGIN 0.0000 0.0000 ;
  SIZE 0.2100 BY 0.0540 ;
  SYMMETRY X Y ;
  SITE i3d_16A ;
  PIN VSS
    DIRECTION INOUT ;
    USE GROUND ;
    PORT
      LAYER BPR ;
        RECT -0.0160 -0.0135 0.2260 0.0135 ;
    END
  END VSS
  PIN VDD
    DIRECTION INOUT ;
    USE POWER ;
    PORT
      LAYER BPR ;
        RECT -0.0160 0.0405 0.2250 0.0675 ;
    END
  END VDD
  PIN A2
    DIRECTION INPUT ;
    USE SIGNAL ;
    PORT
      LAYER M1 ;
        RECT 0.1830 0.0205 0.1950 0.0325 ;
    END
  END A2
  PIN A1
    DIRECTION INPUT ;
    USE SIGNAL ;
    PORT
      LAYER M1 ;
        RECT 0.0150 0.0205 0.0270 0.0325 ;
    END
  END A1
  PIN ZN
    DIRECTION OUTPUT ;
    USE SIGNAL ;
    PORT
      LAYER M1 ;
        RECT 0.1410 0.0025 0.1530 0.0505 ;
    END
  END ZN
END NAND2_X2

MACRO NAND2_X4
  CLASS CORE ;
  FOREIGN NAND2_X4 0 0 ;
  ORIGIN 0.0000 0.0000 ;
  SIZE 0.3780 BY 0.0540 ;
  SYMMETRY X Y ;
  SITE i3d_16A ;
  PIN VSS
    DIRECTION INOUT ;
    USE GROUND ;
    PORT
      LAYER BPR ;
        RECT -0.0160 -0.0135 0.3940 0.0135 ;
    END
  END VSS
  PIN VDD
    DIRECTION INOUT ;
    USE POWER ;
    PORT
      LAYER BPR ;
        RECT -0.0160 0.0405 0.3940 0.0675 ;
    END
  END VDD
  PIN A1
    DIRECTION INPUT ;
    USE SIGNAL ;
    PORT
      LAYER M1 ;
        RECT 0.0150 0.0205 0.0270 0.0325 ;
    END
  END A1
  PIN ZN
    DIRECTION OUTPUT ;
    USE SIGNAL ;
    PORT
      LAYER M1 ;
        RECT 0.2250 0.0025 0.2370 0.0505 ;
    END
  END ZN
  PIN A2
    DIRECTION INPUT ;
    USE SIGNAL ;
    PORT
      LAYER M1 ;
        RECT 0.3510 0.0205 0.3630 0.0325 ;
    END
  END A2
END NAND2_X4

MACRO NAND3_X1
  CLASS CORE ;
  FOREIGN NAND3_X1 0 0 ;
  ORIGIN 0.0000 0.0000 ;
  SIZE 0.1680 BY 0.0540 ;
  SYMMETRY X Y ;
  SITE i3d_16A ;
  PIN VSS
    DIRECTION INOUT ;
    USE GROUND ;
    PORT
      LAYER BPR ;
        RECT -0.0160 -0.0135 0.1840 0.0135 ;
    END
  END VSS
  PIN VDD
    DIRECTION INOUT ;
    USE POWER ;
    PORT
      LAYER BPR ;
        RECT -0.0160 0.0405 0.1840 0.0675 ;
    END
  END VDD
  PIN A2
    DIRECTION INPUT ;
    USE SIGNAL ;
    PORT
      LAYER M1 ;
        RECT 0.0570 0.0205 0.0690 0.0325 ;
    END
  END A2
  PIN A1
    DIRECTION INPUT ;
    USE SIGNAL ;
    PORT
      LAYER M1 ;
        RECT 0.0150 0.0205 0.0270 0.0325 ;
    END
  END A1
  PIN ZN
    DIRECTION OUTPUT ;
    USE SIGNAL ;
    PORT
      LAYER M1 ;
        RECT 0.1410 0.0025 0.1530 0.0325 ;
    END
  END ZN
  PIN A3
    DIRECTION INPUT ;
    USE SIGNAL ;
    PORT
      LAYER M1 ;
        RECT 0.0990 0.0205 0.1110 0.0325 ;
    END
  END A3
END NAND3_X1

MACRO NAND4_X1
  CLASS CORE ;
  FOREIGN NAND4_X1 0 0 ;
  ORIGIN 0.0000 0.0000 ;
  SIZE 0.2100 BY 0.0540 ;
  SYMMETRY X Y ;
  SITE i3d_16A ;
  PIN VSS
    DIRECTION INOUT ;
    USE GROUND ;
    PORT
      LAYER BPR ;
        RECT -0.0160 -0.0135 0.2260 0.0135 ;
    END
  END VSS
  PIN VDD
    DIRECTION INOUT ;
    USE POWER ;
    PORT
      LAYER BPR ;
        RECT -0.0160 0.0405 0.2260 0.0675 ;
    END
  END VDD
  PIN A2
    DIRECTION INPUT ;
    USE SIGNAL ;
    PORT
      LAYER M1 ;
        RECT 0.0570 0.0205 0.0690 0.0325 ;
    END
  END A2
  PIN A1
    DIRECTION INPUT ;
    USE SIGNAL ;
    PORT
      LAYER M1 ;
        RECT 0.0150 0.0205 0.0270 0.0325 ;
    END
  END A1
  PIN ZN
    DIRECTION OUTPUT ;
    USE SIGNAL ;
    PORT
      LAYER M1 ;
        RECT 0.1830 0.0025 0.1950 0.0325 ;
    END
  END ZN
  PIN A3
    DIRECTION INPUT ;
    USE SIGNAL ;
    PORT
      LAYER M1 ;
        RECT 0.0990 0.0205 0.1110 0.0325 ;
    END
  END A3
  PIN A4
    DIRECTION INPUT ;
    USE SIGNAL ;
    PORT
      LAYER M1 ;
        RECT 0.1410 0.0205 0.1530 0.0325 ;
    END
  END A4
END NAND4_X1

MACRO NOR2_X1
  CLASS CORE ;
  FOREIGN NOR2_X1 0 0 ;
  ORIGIN 0.0000 0.0000 ;
  SIZE 0.1260 BY 0.0540 ;
  SYMMETRY X Y ;
  SITE i3d_16A ;
  PIN VDD
    DIRECTION INOUT ;
    USE POWER ;
    PORT
      LAYER BPR ;
        RECT -0.0160 0.0405 0.1420 0.0675 ;
    END
  END VDD
  PIN VSS
    DIRECTION INOUT ;
    USE GROUND ;
    PORT
      LAYER BPR ;
        RECT -0.0160 -0.0135 0.1420 0.0135 ;
    END
  END VSS
  PIN A1
    DIRECTION INPUT ;
    USE SIGNAL ;
    PORT
      LAYER M1 ;
        RECT 0.0150 0.0205 0.0270 0.0325 ;
    END
  END A1
  PIN ZN
    DIRECTION OUTPUT ;
    USE SIGNAL ;
    PORT
      LAYER M1 ;
        RECT 0.0990 0.0025 0.1110 0.0325 ;
    END
  END ZN
  PIN A2
    DIRECTION INPUT ;
    USE SIGNAL ;
    PORT
      LAYER M1 ;
        RECT 0.0570 0.0205 0.0690 0.0325 ;
    END
  END A2
END NOR2_X1

MACRO NOR2_X2
  CLASS CORE ;
  FOREIGN NOR2_X2 0 0 ;
  ORIGIN 0.0000 0.0000 ;
  SIZE 0.2100 BY 0.0540 ;
  SYMMETRY X Y ;
  SITE i3d_16A ;
  PIN VDD
    DIRECTION INOUT ;
    USE POWER ;
    PORT
      LAYER BPR ;
        RECT -0.0160 0.0405 0.2290 0.0675 ;
    END
  END VDD
  PIN VSS
    DIRECTION INOUT ;
    USE GROUND ;
    PORT
      LAYER BPR ;
        RECT -0.0160 -0.0135 0.2310 0.0135 ;
    END
  END VSS
  PIN A1
    DIRECTION INPUT ;
    USE SIGNAL ;
    PORT
      LAYER M1 ;
        RECT 0.0150 0.0205 0.0270 0.0325 ;
    END
  END A1
  PIN ZN
    DIRECTION OUTPUT ;
    USE SIGNAL ;
    PORT
      LAYER M1 ;
        RECT 0.1410 0.0025 0.1530 0.0325 ;
    END
  END ZN
  PIN A2
    DIRECTION INPUT ;
    USE SIGNAL ;
    PORT
      LAYER M1 ;
        RECT 0.1830 0.0205 0.1950 0.0325 ;
    END
  END A2
END NOR2_X2

MACRO NOR2_X4
  CLASS CORE ;
  FOREIGN NOR2_X4 0 0 ;
  ORIGIN 0.0000 0.0000 ;
  SIZE 0.3780 BY 0.0540 ;
  SYMMETRY X Y ;
  SITE i3d_16A ;
  PIN VDD
    DIRECTION INOUT ;
    USE POWER ;
    PORT
      LAYER BPR ;
        RECT -0.0160 0.0405 0.3940 0.0675 ;
    END
  END VDD
  PIN VSS
    DIRECTION INOUT ;
    USE GROUND ;
    PORT
      LAYER BPR ;
        RECT -0.0160 -0.0135 0.3940 0.0135 ;
    END
  END VSS
  PIN A1
    DIRECTION INPUT ;
    USE SIGNAL ;
    PORT
      LAYER M1 ;
        RECT 0.0150 0.0205 0.0270 0.0325 ;
    END
  END A1
  PIN ZN
    DIRECTION OUTPUT ;
    USE SIGNAL ;
    PORT
      LAYER M1 ;
        RECT 0.3090 0.0025 0.3210 0.0325 ;
    END
  END ZN
  PIN A2
    DIRECTION INPUT ;
    USE SIGNAL ;
    PORT
      LAYER M1 ;
        RECT 0.3510 0.0205 0.3630 0.0325 ;
    END
  END A2
END NOR2_X4

MACRO NOR3_X1
  CLASS CORE ;
  FOREIGN NOR3_X1 0 0 ;
  ORIGIN 0.0000 0.0000 ;
  SIZE 0.1680 BY 0.0540 ;
  SYMMETRY X Y ;
  SITE i3d_16A ;
  PIN VDD
    DIRECTION INOUT ;
    USE POWER ;
    PORT
      LAYER BPR ;
        RECT -0.0160 0.0405 0.1840 0.0675 ;
    END
  END VDD
  PIN VSS
    DIRECTION INOUT ;
    USE GROUND ;
    PORT
      LAYER BPR ;
        RECT -0.0160 -0.0135 0.1840 0.0135 ;
    END
  END VSS
  PIN A1
    DIRECTION INPUT ;
    USE SIGNAL ;
    PORT
      LAYER M1 ;
        RECT 0.0150 0.0205 0.0270 0.0325 ;
    END
  END A1
  PIN ZN
    DIRECTION OUTPUT ;
    USE SIGNAL ;
    PORT
      LAYER M1 ;
        RECT 0.0990 0.0025 0.1110 0.0505 ;
    END
  END ZN
  PIN A2
    DIRECTION INPUT ;
    USE SIGNAL ;
    PORT
      LAYER M1 ;
        RECT 0.0570 0.0205 0.0690 0.0325 ;
    END
  END A2
  PIN A3
    DIRECTION INPUT ;
    USE SIGNAL ;
    PORT
      LAYER M1 ;
        RECT 0.1410 0.0205 0.1530 0.0325 ;
    END
  END A3
END NOR3_X1

MACRO NOR4_X1
  CLASS CORE ;
  FOREIGN NOR4_X1 0 0 ;
  ORIGIN 0.0000 0.0000 ;
  SIZE 0.2100 BY 0.0540 ;
  SYMMETRY X Y ;
  SITE i3d_16A ;
  PIN VDD
    DIRECTION INOUT ;
    USE POWER ;
    PORT
      LAYER BPR ;
        RECT -0.0160 0.0405 0.2260 0.0675 ;
    END
  END VDD
  PIN VSS
    DIRECTION INOUT ;
    USE GROUND ;
    PORT
      LAYER BPR ;
        RECT -0.0160 -0.0135 0.2260 0.0135 ;
    END
  END VSS
  PIN A1
    DIRECTION INPUT ;
    USE SIGNAL ;
    PORT
      LAYER M1 ;
        RECT 0.0150 0.0205 0.0270 0.0325 ;
    END
  END A1
  PIN ZN
    DIRECTION OUTPUT ;
    USE SIGNAL ;
    PORT
      LAYER M1 ;
        RECT 0.0990 0.0025 0.1110 0.0505 ;
    END
  END ZN
  PIN A2
    DIRECTION INPUT ;
    USE SIGNAL ;
    PORT
      LAYER M1 ;
        RECT 0.0570 0.0205 0.0690 0.0325 ;
    END
  END A2
  PIN A3
    DIRECTION INPUT ;
    USE SIGNAL ;
    PORT
      LAYER M1 ;
        RECT 0.1410 0.0205 0.1530 0.0325 ;
    END
  END A3
  PIN A4
    DIRECTION INPUT ;
    USE SIGNAL ;
    PORT
      LAYER M1 ;
        RECT 0.1830 0.0205 0.1950 0.0325 ;
    END
  END A4
END NOR4_X1

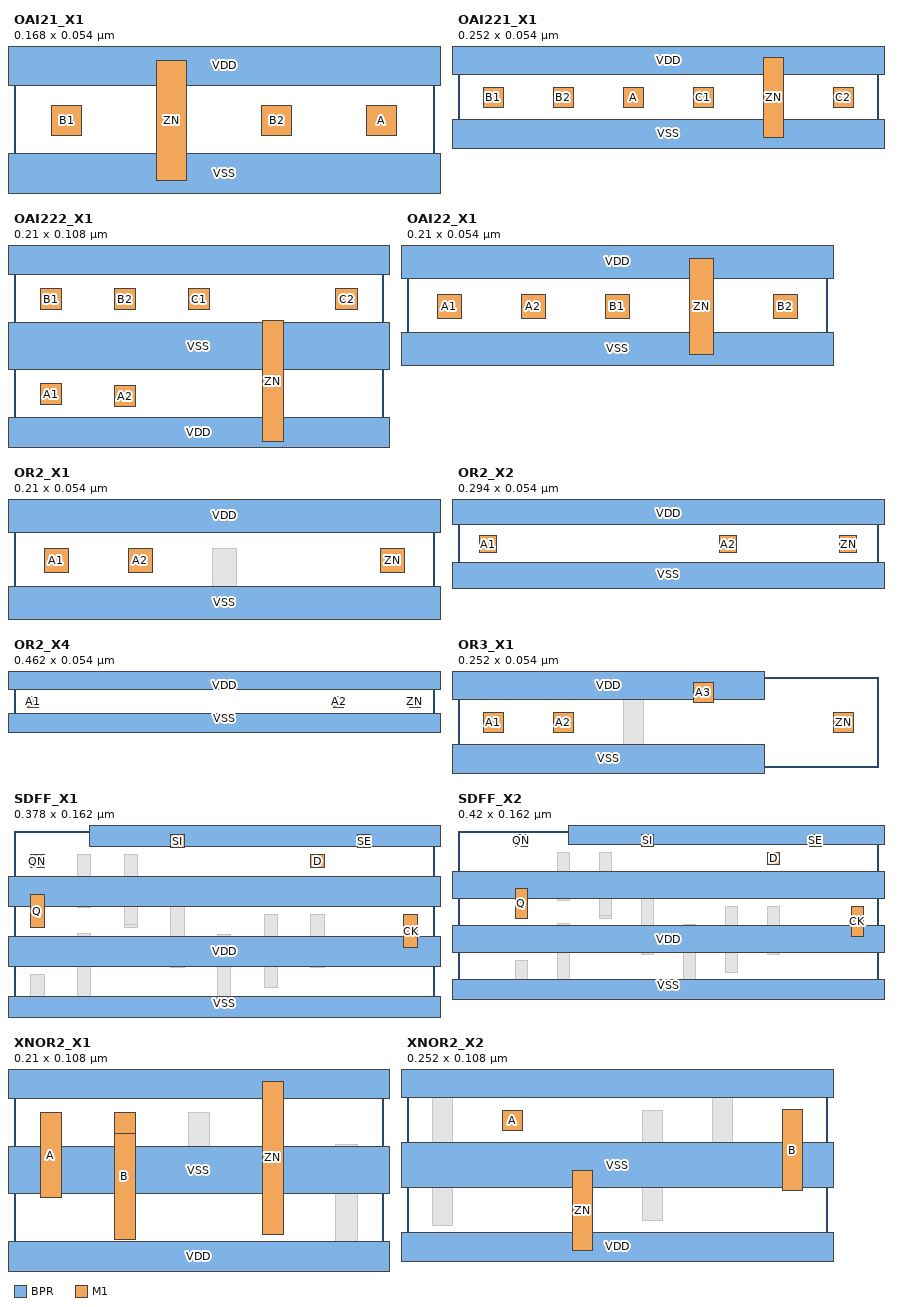
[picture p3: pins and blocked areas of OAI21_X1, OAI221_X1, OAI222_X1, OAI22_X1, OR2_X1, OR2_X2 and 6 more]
MACRO OAI21_X1
  CLASS CORE ;
  FOREIGN OAI21_X1 0 0 ;
  ORIGIN 0.0000 0.0000 ;
  SIZE 0.1680 BY 0.0540 ;
  SYMMETRY X Y ;
  SITE i3d_16A ;
  PIN VDD
    DIRECTION INOUT ;
    USE POWER ;
    PORT
      LAYER BPR ;
        RECT -0.0160 0.0405 0.1840 0.0675 ;
    END
  END VDD
  PIN VSS
    DIRECTION INOUT ;
    USE GROUND ;
    PORT
      LAYER BPR ;
        RECT -0.0160 -0.0135 0.1840 0.0135 ;
    END
  END VSS
  PIN ZN
    DIRECTION OUTPUT ;
    USE SIGNAL ;
    PORT
      LAYER M1 ;
        RECT 0.0570 0.0025 0.0690 0.0505 ;
    END
  END ZN
  PIN B1
    DIRECTION INPUT ;
    USE SIGNAL ;
    PORT
      LAYER M1 ;
        RECT 0.0150 0.0205 0.0270 0.0325 ;
    END
  END B1
  PIN B2
    DIRECTION INPUT ;
    USE SIGNAL ;
    PORT
      LAYER M1 ;
        RECT 0.0990 0.0205 0.1110 0.0325 ;
    END
  END B2
  PIN A
    DIRECTION INPUT ;
    USE SIGNAL ;
    PORT
      LAYER M1 ;
        RECT 0.1410 0.0205 0.1530 0.0325 ;
    END
  END A
END OAI21_X1

MACRO OAI221_X1
  CLASS CORE ;
  FOREIGN OAI221_X1 0 0 ;
  ORIGIN 0.0000 0.0000 ;
  SIZE 0.2520 BY 0.0540 ;
  SYMMETRY X Y ;
  SITE i3d_16A ;
  PIN VSS
    DIRECTION INOUT ;
    USE GROUND ;
    PORT
      LAYER BPR ;
        RECT -0.0160 -0.0135 0.2680 0.0135 ;
    END
  END VSS
  PIN VDD
    DIRECTION INOUT ;
    USE POWER ;
    PORT
      LAYER BPR ;
        RECT -0.0160 0.0405 0.2680 0.0675 ;
    END
  END VDD
  PIN ZN
    DIRECTION OUTPUT ;
    USE SIGNAL ;
    PORT
      LAYER M1 ;
        RECT 0.1830 0.0025 0.1950 0.0505 ;
    END
  END ZN
  PIN C1
    DIRECTION INPUT ;
    USE SIGNAL ;
    PORT
      LAYER M1 ;
        RECT 0.1410 0.0205 0.1530 0.0325 ;
    END
  END C1
  PIN A
    DIRECTION INPUT ;
    USE SIGNAL ;
    PORT
      LAYER M1 ;
        RECT 0.0990 0.0205 0.1110 0.0325 ;
    END
  END A
  PIN B2
    DIRECTION INPUT ;
    USE SIGNAL ;
    PORT
      LAYER M1 ;
        RECT 0.0570 0.0205 0.0690 0.0325 ;
    END
  END B2
  PIN B1
    DIRECTION INPUT ;
    USE SIGNAL ;
    PORT
      LAYER M1 ;
        RECT 0.0150 0.0205 0.0270 0.0325 ;
    END
  END B1
  PIN C2
    DIRECTION INPUT ;
    USE SIGNAL ;
    PORT
      LAYER M1 ;
        RECT 0.2250 0.0205 0.2370 0.0325 ;
    END
  END C2
END OAI221_X1

MACRO OAI222_X1
  CLASS CORE ;
  FOREIGN OAI222_X1 0 0 ;
  ORIGIN 0.0000 0.0000 ;
  SIZE 0.2100 BY 0.1080 ;
  SYMMETRY X Y ;
  SITE i3d_16A ;
  PIN VDD
    DIRECTION INOUT ;
    USE POWER ;
    PORT
      LAYER BPR ;
        RECT -0.0160 0.0945 0.2260 0.1215 ;
        RECT -0.0160 -0.0135 0.2260 0.0135 ;
    END
  END VDD
  PIN VSS
    DIRECTION INOUT ;
    USE GROUND ;
    PORT
      LAYER BPR ;
        RECT -0.0160 0.0405 0.2260 0.0675 ;
    END
  END VSS
  PIN ZN
    DIRECTION OUTPUT ;
    USE SIGNAL ;
    PORT
      LAYER M1 ;
        RECT 0.1410 -0.0005 0.1530 0.0685 ;
    END
  END ZN
  PIN C2
    DIRECTION INPUT ;
    USE SIGNAL ;
    PORT
      LAYER M1 ;
        RECT 0.1830 0.0745 0.1950 0.0865 ;
    END
  END C2
  PIN C1
    DIRECTION INPUT ;
    USE SIGNAL ;
    PORT
      LAYER M1 ;
        RECT 0.0990 0.0745 0.1110 0.0865 ;
    END
  END C1
  PIN B2
    DIRECTION INPUT ;
    USE SIGNAL ;
    PORT
      LAYER M1 ;
        RECT 0.0570 0.0745 0.0690 0.0865 ;
    END
  END B2
  PIN B1
    DIRECTION INPUT ;
    USE SIGNAL ;
    PORT
      LAYER M1 ;
        RECT 0.0150 0.0745 0.0270 0.0865 ;
    END
  END B1
  PIN A1
    DIRECTION INPUT ;
    USE SIGNAL ;
    PORT
      LAYER M1 ;
        RECT 0.0150 0.0205 0.0270 0.0325 ;
    END
  END A1
  PIN A2
    DIRECTION INPUT ;
    USE SIGNAL ;
    PORT
      LAYER M1 ;
        RECT 0.0570 0.0195 0.0690 0.0315 ;
    END
  END A2
END OAI222_X1

MACRO OAI22_X1
  CLASS CORE ;
  FOREIGN OAI22_X1 0 0 ;
  ORIGIN 0.0000 0.0000 ;
  SIZE 0.2100 BY 0.0540 ;
  SYMMETRY X Y ;
  SITE i3d_16A ;
  PIN VDD
    DIRECTION INOUT ;
    USE POWER ;
    PORT
      LAYER BPR ;
        RECT -0.0160 0.0405 0.2260 0.0675 ;
    END
  END VDD
  PIN VSS
    DIRECTION INOUT ;
    USE GROUND ;
    PORT
      LAYER BPR ;
        RECT -0.0160 -0.0135 0.2260 0.0135 ;
    END
  END VSS
  PIN ZN
    DIRECTION OUTPUT ;
    USE SIGNAL ;
    PORT
      LAYER M1 ;
        RECT 0.1410 0.0025 0.1530 0.0505 ;
    END
  END ZN
  PIN A1
    DIRECTION INPUT ;
    USE SIGNAL ;
    PORT
      LAYER M1 ;
        RECT 0.0150 0.0205 0.0270 0.0325 ;
    END
  END A1
  PIN A2
    DIRECTION INPUT ;
    USE SIGNAL ;
    PORT
      LAYER M1 ;
        RECT 0.0570 0.0205 0.0690 0.0325 ;
    END
  END A2
  PIN B2
    DIRECTION INPUT ;
    USE SIGNAL ;
    PORT
      LAYER M1 ;
        RECT 0.1830 0.0205 0.1950 0.0325 ;
    END
  END B2
  PIN B1
    DIRECTION INPUT ;
    USE SIGNAL ;
    PORT
      LAYER M1 ;
        RECT 0.0990 0.0205 0.1110 0.0325 ;
    END
  END B1
END OAI22_X1

MACRO OR2_X1
  CLASS CORE ;
  FOREIGN OR2_X1 0 0 ;
  ORIGIN 0.0000 0.0000 ;
  SIZE 0.2100 BY 0.0540 ;
  SYMMETRY X Y ;
  SITE i3d_16A ;
  PIN VDD
    DIRECTION INOUT ;
    USE POWER ;
    PORT
      LAYER BPR ;
        RECT -0.0160 0.0405 0.2260 0.0675 ;
    END
  END VDD
  PIN VSS
    DIRECTION INOUT ;
    USE GROUND ;
    PORT
      LAYER BPR ;
        RECT -0.0160 -0.0135 0.2260 0.0135 ;
    END
  END VSS
  PIN A1
    DIRECTION INPUT ;
    USE SIGNAL ;
    PORT
      LAYER M1 ;
        RECT 0.0150 0.0205 0.0270 0.0325 ;
    END
  END A1
  PIN A2
    DIRECTION INPUT ;
    USE SIGNAL ;
    PORT
      LAYER M1 ;
        RECT 0.0570 0.0205 0.0690 0.0325 ;
    END
  END A2
  PIN ZN
    DIRECTION OUTPUT ;
    USE SIGNAL ;
    PORT
      LAYER M1 ;
        RECT 0.1830 0.0205 0.1950 0.0325 ;
    END
  END ZN
  OBS
    LAYER M1 ;
      RECT 0.0990 0.0025 0.1110 0.0325 ;
  END
END OR2_X1

MACRO OR2_X2
  CLASS CORE ;
  FOREIGN OR2_X2 0 0 ;
  ORIGIN 0.0000 0.0000 ;
  SIZE 0.2940 BY 0.0540 ;
  SYMMETRY X Y ;
  SITE i3d_16A ;
  PIN VDD
    DIRECTION INOUT ;
    USE POWER ;
    PORT
      LAYER BPR ;
        RECT -0.0160 0.0405 0.3100 0.0675 ;
    END
  END VDD
  PIN VSS
    DIRECTION INOUT ;
    USE GROUND ;
    PORT
      LAYER BPR ;
        RECT -0.0160 -0.0135 0.3100 0.0135 ;
    END
  END VSS
  PIN A1
    DIRECTION INPUT ;
    USE SIGNAL ;
    PORT
      LAYER M1 ;
        RECT 0.0150 0.0205 0.0270 0.0325 ;
    END
  END A1
  PIN A2
    DIRECTION INPUT ;
    USE SIGNAL ;
    PORT
      LAYER M1 ;
        RECT 0.1830 0.0205 0.1950 0.0325 ;
    END
  END A2
  PIN ZN
    DIRECTION OUTPUT ;
    USE SIGNAL ;
    PORT
      LAYER M1 ;
        RECT 0.2670 0.0205 0.2790 0.0325 ;
    END
  END ZN
END OR2_X2

MACRO OR2_X4
  CLASS CORE ;
  FOREIGN OR2_X4 0 0 ;
  ORIGIN 0.0000 0.0000 ;
  SIZE 0.4620 BY 0.0540 ;
  SYMMETRY X Y ;
  SITE i3d_16A ;
  PIN VDD
    DIRECTION INOUT ;
    USE POWER ;
    PORT
      LAYER BPR ;
        RECT -0.0160 0.0405 0.4780 0.0675 ;
    END
  END VDD
  PIN VSS
    DIRECTION INOUT ;
    USE GROUND ;
    PORT
      LAYER BPR ;
        RECT -0.0160 -0.0135 0.4780 0.0135 ;
    END
  END VSS
  PIN A1
    DIRECTION INPUT ;
    USE SIGNAL ;
    PORT
      LAYER M1 ;
        RECT 0.0150 0.0205 0.0270 0.0325 ;
    END
  END A1
  PIN A2
    DIRECTION INPUT ;
    USE SIGNAL ;
    PORT
      LAYER M1 ;
        RECT 0.3510 0.0205 0.3630 0.0325 ;
    END
  END A2
  PIN ZN
    DIRECTION OUTPUT ;
    USE SIGNAL ;
    PORT
      LAYER M1 ;
        RECT 0.4350 0.0205 0.4470 0.0325 ;
    END
  END ZN
END OR2_X4

MACRO OR3_X1
  CLASS CORE ;
  FOREIGN OR3_X1 0 0 ;
  ORIGIN 0.0000 0.0000 ;
  SIZE 0.2520 BY 0.0540 ;
  SYMMETRY X Y ;
  SITE i3d_16A ;
  PIN VSS
    DIRECTION INOUT ;
    USE GROUND ;
    PORT
      LAYER BPR ;
        RECT -0.0160 -0.0135 0.1840 0.0135 ;
    END
  END VSS
  PIN VDD
    DIRECTION INOUT ;
    USE POWER ;
    PORT
      LAYER BPR ;
        RECT -0.0160 0.0405 0.1840 0.0675 ;
    END
  END VDD
  PIN A1
    DIRECTION INPUT ;
    USE SIGNAL ;
    PORT
      LAYER M1 ;
        RECT 0.0150 0.0205 0.0270 0.0325 ;
    END
  END A1
  PIN A3
    DIRECTION INPUT ;
    USE SIGNAL ;
    PORT
      LAYER M1 ;
        RECT 0.1410 0.0385 0.1530 0.0505 ;
    END
  END A3
  PIN A2
    DIRECTION INPUT ;
    USE SIGNAL ;
    PORT
      LAYER M1 ;
        RECT 0.0570 0.0205 0.0690 0.0325 ;
    END
  END A2
  PIN ZN
    DIRECTION OUTPUT ;
    USE SIGNAL ;
    PORT
      LAYER M1 ;
        RECT 0.2250 0.0205 0.2370 0.0325 ;
    END
  END ZN
  OBS
    LAYER M1 ;
      RECT 0.0990 0.0025 0.1110 0.0505 ;
  END
END OR3_X1

MACRO SDFF_X1
  CLASS CORE ;
  FOREIGN SDFF_X1 0 0 ;
  ORIGIN 0.0000 0.0000 ;
  SIZE 0.3780 BY 0.1620 ;
  SYMMETRY X Y ;
  SITE i3d_16A ;
  PIN VSS
    DIRECTION INOUT ;
    USE GROUND ;
    PORT
      LAYER BPR ;
        RECT -0.0160 0.0945 0.3930 0.1215 ;
        RECT -0.0160 -0.0135 0.3930 0.0135 ;
    END
  END VSS
  PIN VDD
    DIRECTION INOUT ;
    USE POWER ;
    PORT
      LAYER BPR ;
        RECT -0.0160 0.0405 0.3930 0.0675 ;
        RECT 0.0680 0.1485 0.3910 0.1755 ;
    END
  END VDD
  PIN QN
    DIRECTION OUTPUT ;
    USE SIGNAL ;
    PORT
      LAYER M1 ;
        RECT 0.0150 0.1290 0.0270 0.1410 ;
    END
  END QN
  PIN Q
    DIRECTION OUTPUT ;
    USE SIGNAL ;
    PORT
      LAYER M1 ;
        RECT 0.0150 0.0750 0.0270 0.1050 ;
    END
  END Q
  PIN CK
    DIRECTION INPUT ;
    USE CLOCK ;
    PORT
      LAYER M1 ;
        RECT 0.3510 0.0570 0.3630 0.0870 ;
    END
  END CK
  PIN SE
    DIRECTION INPUT ;
    USE SIGNAL ;
    PORT
      LAYER M1 ;
        RECT 0.3090 0.1470 0.3210 0.1590 ;
    END
  END SE
  PIN SI
    DIRECTION INPUT ;
    USE SIGNAL ;
    PORT
      LAYER M1 ;
        RECT 0.1410 0.1470 0.1530 0.1590 ;
    END
  END SI
  PIN D
    DIRECTION INPUT ;
    USE SIGNAL ;
    PORT
      LAYER M1 ;
        RECT 0.2670 0.1290 0.2790 0.1410 ;
    END
  END D
  OBS
    LAYER M1 ;
      RECT 0.0990 0.0750 0.1110 0.0870 ;
      RECT 0.0570 0.0930 0.0690 0.1410 ;
      RECT 0.0150 0.0030 0.0270 0.0330 ;
      RECT 0.0570 0.0030 0.0690 0.0700 ;
      RECT 0.0990 0.0775 0.1110 0.1410 ;
      RECT 0.1830 0.0030 0.1950 0.0690 ;
      RECT 0.1410 0.0390 0.1530 0.1050 ;
      RECT 0.2670 0.0390 0.2790 0.0870 ;
      RECT 0.2250 0.0210 0.2370 0.0870 ;
  END
END SDFF_X1

MACRO SDFF_X2
  CLASS CORE ;
  FOREIGN SDFF_X2 0 0 ;
  ORIGIN 0.0000 0.0000 ;
  SIZE 0.4200 BY 0.1620 ;
  SYMMETRY X Y ;
  SITE i3d_16A ;
  PIN VDD
    DIRECTION INOUT ;
    USE POWER ;
    PORT
      LAYER BPR ;
        RECT -0.0160 0.0405 0.4350 0.0675 ;
        RECT 0.1100 0.1485 0.4330 0.1755 ;
    END
  END VDD
  PIN VSS
    DIRECTION INOUT ;
    USE GROUND ;
    PORT
      LAYER BPR ;
        RECT -0.0160 0.0945 0.4350 0.1215 ;
        RECT -0.0160 -0.0135 0.4350 0.0135 ;
    END
  END VSS
  PIN SI
    DIRECTION INPUT ;
    USE SIGNAL ;
    PORT
      LAYER M1 ;
        RECT 0.1830 0.1470 0.1950 0.1590 ;
    END
  END SI
  PIN D
    DIRECTION INPUT ;
    USE SIGNAL ;
    PORT
      LAYER M1 ;
        RECT 0.3090 0.1290 0.3210 0.1410 ;
    END
  END D
  PIN Q
    DIRECTION OUTPUT ;
    USE SIGNAL ;
    PORT
      LAYER M1 ;
        RECT 0.0570 0.0750 0.0690 0.1050 ;
    END
  END Q
  PIN QN
    DIRECTION OUTPUT ;
    USE SIGNAL ;
    PORT
      LAYER M1 ;
        RECT 0.0570 0.1470 0.0690 0.1590 ;
    END
  END QN
  PIN SE
    DIRECTION INPUT ;
    USE SIGNAL ;
    PORT
      LAYER M1 ;
        RECT 0.3510 0.1470 0.3630 0.1590 ;
    END
  END SE
  PIN CK
    DIRECTION INPUT ;
    USE CLOCK ;
    PORT
      LAYER M1 ;
        RECT 0.3930 0.0570 0.4050 0.0870 ;
    END
  END CK
  OBS
    LAYER M1 ;
      RECT 0.1410 0.0750 0.1530 0.0870 ;
      RECT 0.0990 0.0030 0.1110 0.0700 ;
      RECT 0.2670 0.0210 0.2790 0.0870 ;
      RECT 0.1830 0.0390 0.1950 0.1050 ;
      RECT 0.2250 0.0030 0.2370 0.0690 ;
      RECT 0.1410 0.0775 0.1530 0.1410 ;
      RECT 0.0990 0.0930 0.1110 0.1410 ;
      RECT 0.3090 0.0390 0.3210 0.0870 ;
      RECT 0.0570 0.0030 0.0690 0.0330 ;
  END
END SDFF_X2

MACRO XNOR2_X1
  CLASS CORE ;
  FOREIGN XNOR2_X1 0 0 ;
  ORIGIN 0.0000 0.0000 ;
  SIZE 0.2100 BY 0.1080 ;
  SYMMETRY X Y ;
  SITE i3d_16A ;
  PIN VSS
    DIRECTION INOUT ;
    USE GROUND ;
    PORT
      LAYER BPR ;
        RECT -0.0160 0.0405 0.2260 0.0675 ;
    END
  END VSS
  PIN VDD
    DIRECTION INOUT ;
    USE POWER ;
    PORT
      LAYER BPR ;
        RECT -0.0160 -0.0135 0.2260 0.0135 ;
        RECT -0.0160 0.0945 0.2260 0.1215 ;
    END
  END VDD
  PIN A
    DIRECTION INPUT ;
    USE SIGNAL ;
    PORT
      LAYER M1 ;
        RECT 0.0150 0.0385 0.0270 0.0865 ;
    END
  END A
  PIN ZN
    DIRECTION OUTPUT ;
    USE SIGNAL ;
    PORT
      LAYER M1 ;
        RECT 0.1410 0.0175 0.1530 0.1045 ;
    END
  END ZN
  PIN B
    DIRECTION INPUT ;
    USE SIGNAL ;
    PORT
      LAYER M1 ;
        RECT 0.0570 0.0145 0.0690 0.0865 ;
        RECT 0.0570 0.0745 0.0690 0.0865 ;
    END
  END B
  OBS
    LAYER M1 ;
      RECT 0.0990 0.0565 0.1110 0.0865 ;
      RECT 0.1830 0.0045 0.1950 0.0685 ;
  END
END XNOR2_X1

MACRO XNOR2_X2
  CLASS CORE ;
  FOREIGN XNOR2_X2 0 0 ;
  ORIGIN 0.0000 0.0000 ;
  SIZE 0.2520 BY 0.1080 ;
  SYMMETRY X Y ;
  SITE i3d_16A ;
  PIN VDD
    DIRECTION INOUT ;
    USE POWER ;
    PORT
      LAYER BPR ;
        RECT -0.0160 -0.0135 0.2680 0.0135 ;
        RECT -0.0160 0.0945 0.2670 0.1215 ;
    END
  END VDD
  PIN VSS
    DIRECTION INOUT ;
    USE GROUND ;
    PORT
      LAYER BPR ;
        RECT -0.0160 0.0405 0.2680 0.0675 ;
    END
  END VSS
  PIN A
    DIRECTION INPUT ;
    USE SIGNAL ;
    PORT
      LAYER M1 ;
        RECT 0.0570 0.0745 0.0690 0.0865 ;
    END
  END A
  PIN B
    DIRECTION INPUT ;
    USE SIGNAL ;
    PORT
      LAYER M1 ;
        RECT 0.2250 0.0385 0.2370 0.0875 ;
    END
  END B
  PIN ZN
    DIRECTION OUTPUT ;
    USE SIGNAL ;
    PORT
      LAYER M1 ;
        RECT 0.0990 0.0025 0.1110 0.0505 ;
    END
  END ZN
  OBS
    LAYER M1 ;
      RECT 0.1830 0.0565 0.1950 0.1045 ;
      RECT 0.0150 0.0175 0.0270 0.1045 ;
      RECT 0.1410 0.0205 0.1530 0.0865 ;
  END
END XNOR2_X2

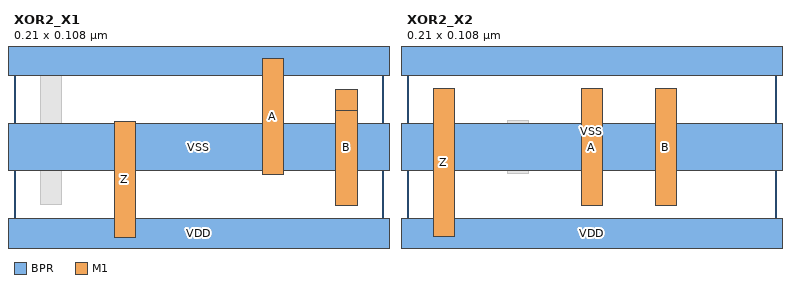
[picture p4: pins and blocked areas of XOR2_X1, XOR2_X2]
MACRO XOR2_X1
  CLASS CORE ;
  FOREIGN XOR2_X1 0 0 ;
  ORIGIN 0.0000 0.0000 ;
  SIZE 0.2100 BY 0.1080 ;
  SYMMETRY X Y ;
  SITE i3d_16A ;
  PIN VDD
    DIRECTION INOUT ;
    USE POWER ;
    PORT
      LAYER BPR ;
        RECT -0.0160 0.0945 0.2260 0.1215 ;
        RECT -0.0160 -0.0135 0.2260 0.0135 ;
    END
  END VDD
  PIN VSS
    DIRECTION INOUT ;
    USE GROUND ;
    PORT
      LAYER BPR ;
        RECT -0.0160 0.0405 0.2260 0.0675 ;
    END
  END VSS
  PIN Z
    DIRECTION OUTPUT ;
    USE SIGNAL ;
    PORT
      LAYER M1 ;
        RECT 0.0570 0.0025 0.0690 0.0685 ;
    END
  END Z
  PIN A
    DIRECTION INPUT ;
    USE SIGNAL ;
    PORT
      LAYER M1 ;
        RECT 0.1410 0.0385 0.1530 0.1045 ;
    END
  END A
  PIN B
    DIRECTION INPUT ;
    USE SIGNAL ;
    PORT
      LAYER M1 ;
        RECT 0.1830 0.0745 0.1950 0.0865 ;
        RECT 0.1830 0.0205 0.1950 0.0865 ;
    END
  END B
  OBS
    LAYER M1 ;
      RECT 0.0150 0.0215 0.0270 0.1045 ;
  END
END XOR2_X1

MACRO XOR2_X2
  CLASS CORE ;
  FOREIGN XOR2_X2 0 0 ;
  ORIGIN 0.0000 0.0000 ;
  SIZE 0.2100 BY 0.1080 ;
  SYMMETRY X Y ;
  SITE i3d_16A ;
  PIN VDD
    DIRECTION INOUT ;
    USE POWER ;
    PORT
      LAYER BPR ;
        RECT -0.0160 -0.0135 0.2260 0.0135 ;
        RECT -0.0160 0.0945 0.2260 0.1215 ;
    END
  END VDD
  PIN VSS
    DIRECTION INOUT ;
    USE GROUND ;
    PORT
      LAYER BPR ;
        RECT -0.0160 0.0405 0.2260 0.0675 ;
    END
  END VSS
  PIN Z
    DIRECTION OUTPUT ;
    USE SIGNAL ;
    PORT
      LAYER M1 ;
        RECT 0.0150 0.0030 0.0270 0.0870 ;
    END
  END Z
  PIN B
    DIRECTION INPUT ;
    USE SIGNAL ;
    PORT
      LAYER M1 ;
        RECT 0.1410 0.0210 0.1530 0.0870 ;
    END
  END B
  PIN A
    DIRECTION INPUT ;
    USE SIGNAL ;
    PORT
      LAYER M1 ;
        RECT 0.0990 0.0210 0.1110 0.0870 ;
    END
  END A
  OBS
    LAYER M1 ;
      RECT 0.0570 0.0390 0.0690 0.0690 ;
  END
END XOR2_X2

END LIBRARY
